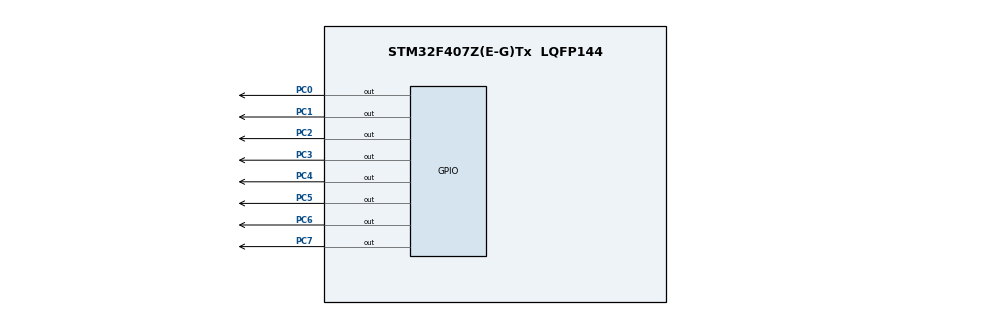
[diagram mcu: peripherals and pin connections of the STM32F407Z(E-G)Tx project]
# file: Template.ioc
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Mcu.Family=STM32F4
Mcu.Name=STM32F407Z(E-G)Tx
Mcu.Package=LQFP144
NVIC.PriorityGroup=NVIC_PRIORITYGROUP_4
PA13.Mode=Serial_Wire
PA13.Signal=SYS_JTMS-SWDIO
PA14.Mode=Serial_Wire
PA14.Signal=SYS_JTCK-SWCLK
PC0.PinState=GPIO_PIN_SET
PC0.Signal=GPIO_Output
PC1.PinState=GPIO_PIN_SET
PC1.Signal=GPIO_Output
PC2.PinState=GPIO_PIN_SET
PC2.Signal=GPIO_Output
PC3.PinState=GPIO_PIN_SET
PC3.Signal=GPIO_Output
PC4.PinState=GPIO_PIN_SET
PC4.Signal=GPIO_Output
PC5.PinState=GPIO_PIN_SET
PC5.Signal=GPIO_Output
PC6.PinState=GPIO_PIN_SET
PC6.Signal=GPIO_Output
PC7.PinState=GPIO_PIN_SET
PC7.Signal=GPIO_Output
PH0-OSC_IN.Mode=HSE-External-Oscillator
PH0-OSC_IN.Signal=RCC_OSC_IN
PH1-OSC_OUT.Mode=HSE-External-Oscillator
PH1-OSC_OUT.Signal=RCC_OSC_OUT
ProjectManager.HeapSize=0x200
ProjectManager.StackSize=0x400
ProjectManager.TargetToolchain=MDK-ARM V5.32
RCC.48MHZClocksFreq_Value=84000000
RCC.AHBFreq_Value=168000000
RCC.APB1CLKDivider=RCC_HCLK_DIV4
RCC.APB1Freq_Value=42000000
RCC.APB1TimFreq_Value=84000000
RCC.APB2CLKDivider=RCC_HCLK_DIV2
RCC.APB2Freq_Value=84000000
RCC.APB2TimFreq_Value=168000000
RCC.CortexFreq_Value=168000000
RCC.HCLKFreq_Value=168000000
RCC.HSE_VALUE=8000000
RCC.HSI_VALUE=16000000
RCC.LSE_VALUE=32768
RCC.PLLM=8
RCC.PLLN=336
RCC.PLLSourceVirtual=RCC_PLLSOURCE_HSE
RCC.SYSCLKFreq_VALUE=168000000
RCC.SYSCLKSource=RCC_SYSCLKSOURCE_PLLCLK
RCC.VCOOutputFreq_Value=336000000
board=custom

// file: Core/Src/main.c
/* USER CODE BEGIN Header */
/**
  ******************************************************************************
  * @file           : main.c
  * @brief          : Main program body
  ******************************************************************************
  * @attention
  *
  * Copyright (c) 2025 STMicroelectronics.
  * All rights reserved.
  *
  * This software is licensed under terms that can be found in the LICENSE file
  * in the root directory of this software component.
  * If no LICENSE file comes with this software, it is provided AS-IS.
  *
  ******************************************************************************
  */
/* USER CODE END Header */
#include "main.h"

void SystemClock_Config(void);

int main(void)
{

  /* MCU Configuration--------------------------------------------------------*/

  /* Reset of all peripherals, Initializes the Flash interface and the Systick. */
  HAL_Init();

  /* Configure the system clock */
  SystemClock_Config();

  /* USER CODE BEGIN SysInit */
	Delay_Init();
  /* USER CODE END SysInit */

  /* Initialize all configured peripherals */

  /* Infinite loop */
  while (1)
  {

  }
}

void SystemClock_Config(void)
{
  RCC_OscInitTypeDef RCC_OscInitStruct = {0};
  RCC_ClkInitTypeDef RCC_ClkInitStruct = {0};

  /** Configure the main internal regulator output voltage
  */
  __HAL_RCC_PWR_CLK_ENABLE();
  __HAL_PWR_VOLTAGESCALING_CONFIG(PWR_REGULATOR_VOLTAGE_SCALE1);

  /** Initializes the RCC Oscillators according to the specified parameters
  * in the RCC_OscInitTypeDef structure.
  */
  RCC_OscInitStruct.OscillatorType = RCC_OSCILLATORTYPE_HSI;
  RCC_OscInitStruct.HSIState = RCC_HSI_ON;
  RCC_OscInitStruct.HSICalibrationValue = RCC_HSICALIBRATION_DEFAULT;
  RCC_OscInitStruct.PLL.PLLState = RCC_PLL_NONE;
  if (HAL_RCC_OscConfig(&RCC_OscInitStruct) != HAL_OK)
  {
    Error_Handler();
  }

  /** Initializes the CPU, AHB and APB buses clocks
  */
  RCC_ClkInitStruct.ClockType = RCC_CLOCKTYPE_HCLK|RCC_CLOCKTYPE_SYSCLK
                              |RCC_CLOCKTYPE_PCLK1|RCC_CLOCKTYPE_PCLK2;
  RCC_ClkInitStruct.SYSCLKSource = RCC_SYSCLKSOURCE_HSI;
  RCC_ClkInitStruct.AHBCLKDivider = RCC_SYSCLK_DIV1;
  RCC_ClkInitStruct.APB1CLKDivider = RCC_HCLK_DIV1;
  RCC_ClkInitStruct.APB2CLKDivider = RCC_HCLK_DIV1;

  if (HAL_RCC_ClockConfig(&RCC_ClkInitStruct, FLASH_LATENCY_0) != HAL_OK)
  {
    Error_Handler();
  }
}

void Error_Handler(void)
{
  __disable_irq();
  while (1)
  {
  }
}
